VERSION 5.7 ;
  NOWIREEXTENSIONATPIN ON ;
  DIVIDERCHAR "/" ;
  BUSBITCHARS "[]" ;
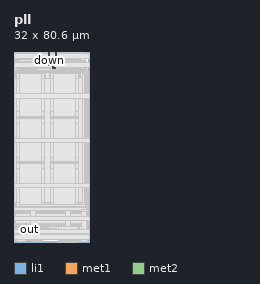
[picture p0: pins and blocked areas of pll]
MACRO pll
  CLASS BLOCK ;
  FOREIGN pll ;
  ORIGIN -0.200 -0.200 ;
  SIZE 32.000 BY 80.600 ;
  PIN down
    DIRECTION INPUT ;
    ANTENNAGATEAREA 0.075000 ;
    PORT
      LAYER li1 ;
        RECT 14.990 75.030 15.320 75.200 ;
      LAYER met1 ;
        RECT 14.900 76.850 15.400 77.350 ;
        RECT 14.950 75.000 15.350 76.850 ;
      LAYER met2 ;
        RECT 14.900 76.850 15.400 80.800 ;
    END
  END down
  PIN up
    DIRECTION INPUT ;
    ANTENNAGATEAREA 0.300000 ;
    PORT
      LAYER li1 ;
        RECT 17.790 75.430 18.120 75.600 ;
        RECT 17.310 73.790 17.640 73.960 ;
      LAYER met1 ;
        RECT 17.750 75.400 18.200 75.750 ;
        RECT 16.950 73.650 17.650 74.050 ;
      LAYER met2 ;
        RECT 17.800 75.750 18.300 80.800 ;
        RECT 16.600 75.350 18.300 75.750 ;
        RECT 16.600 74.050 16.800 75.350 ;
        RECT 16.600 73.650 17.600 74.050 ;
    END
  END up
  PIN out
    DIRECTION OUTPUT ;
    USE CLOCK ;
    ANTENNADIFFAREA 0.310300 ;
    PORT
      LAYER li1 ;
        RECT 6.310 4.930 6.770 5.100 ;
        RECT 6.290 4.090 6.980 4.260 ;
      LAYER met1 ;
        RECT 6.330 4.900 6.750 5.130 ;
        RECT 6.350 4.290 6.900 4.900 ;
        RECT 6.310 4.060 6.960 4.290 ;
        RECT 6.350 4.050 6.900 4.060 ;
      LAYER met2 ;
        RECT 6.350 4.250 6.900 6.650 ;
    END
  END out
  OBS
      LAYER nwell ;
        RECT 18.950 76.290 24.650 76.350 ;
      LAYER pwell ;
        RECT 14.100 73.600 16.210 75.890 ;
      LAYER nwell ;
        RECT 16.400 73.100 24.650 76.290 ;
        RECT 18.950 73.050 24.650 73.100 ;
      LAYER pwell ;
        RECT 0.200 6.800 31.700 72.750 ;
        RECT 0.200 6.750 31.390 6.800 ;
      LAYER nwell ;
        RECT 6.000 4.200 8.500 4.500 ;
      LAYER pwell ;
        RECT 8.500 4.200 12.400 6.450 ;
      LAYER nwell ;
        RECT 6.000 3.200 8.550 4.200 ;
        RECT 7.000 3.150 8.550 3.200 ;
      LAYER pwell ;
        RECT 8.550 3.150 12.400 4.200 ;
        RECT 8.500 0.550 12.400 3.150 ;
      LAYER nwell ;
        RECT 15.750 5.200 17.650 5.210 ;
        RECT 19.200 5.200 27.100 6.150 ;
        RECT 15.750 1.910 27.100 5.200 ;
        RECT 17.600 1.900 27.100 1.910 ;
        RECT 19.200 0.200 27.100 1.900 ;
      LAYER pwell ;
        RECT 28.300 1.850 30.410 5.140 ;
      LAYER li1 ;
        RECT 1.050 80.300 28.050 80.600 ;
        RECT 1.050 77.900 1.350 80.300 ;
        RECT 1.650 79.200 2.150 79.700 ;
        RECT 1.650 78.450 2.150 78.950 ;
        RECT 27.750 77.900 28.050 80.300 ;
        RECT 1.050 77.600 28.050 77.900 ;
        RECT 2.600 76.650 13.100 76.950 ;
        RECT 25.620 76.750 30.660 76.920 ;
        RECT 2.600 73.050 2.900 76.650 ;
        RECT 3.550 76.020 3.880 76.190 ;
        RECT 4.650 76.020 4.980 76.190 ;
        RECT 10.650 76.020 10.980 76.190 ;
        RECT 11.750 76.020 12.080 76.190 ;
        RECT 3.360 74.810 3.530 75.850 ;
        RECT 3.900 74.810 4.070 75.850 ;
        RECT 4.460 74.810 4.630 75.850 ;
        RECT 5.000 74.810 5.170 75.850 ;
        RECT 6.290 75.080 6.620 75.250 ;
        RECT 7.370 75.080 7.700 75.250 ;
        RECT 8.450 75.080 8.780 75.250 ;
        RECT 9.530 75.080 9.860 75.250 ;
        RECT 5.560 73.870 5.730 74.910 ;
        RECT 6.100 73.870 6.270 74.910 ;
        RECT 6.640 73.870 6.810 74.910 ;
        RECT 7.180 73.870 7.350 74.910 ;
        RECT 7.720 73.870 7.890 74.910 ;
        RECT 8.260 73.870 8.430 74.910 ;
        RECT 8.800 73.870 8.970 74.910 ;
        RECT 9.340 73.870 9.510 74.910 ;
        RECT 9.880 73.870 10.050 74.910 ;
        RECT 10.460 74.810 10.630 75.850 ;
        RECT 11.000 74.810 11.170 75.850 ;
        RECT 11.560 74.810 11.730 75.850 ;
        RECT 12.100 74.810 12.270 75.850 ;
        RECT 5.750 73.530 6.080 73.700 ;
        RECT 6.830 73.530 7.160 73.700 ;
        RECT 7.910 73.530 8.240 73.700 ;
        RECT 8.990 73.530 9.320 73.700 ;
        RECT 12.800 73.050 13.100 76.650 ;
        RECT 16.580 75.940 18.850 76.110 ;
        RECT 14.280 75.540 16.030 75.710 ;
        RECT 14.280 73.950 14.450 75.540 ;
        RECT 14.850 74.320 15.020 74.860 ;
        RECT 15.290 74.320 15.460 74.860 ;
        RECT 15.860 73.950 16.030 75.540 ;
        RECT 14.280 73.780 16.030 73.950 ;
        RECT 16.580 73.450 16.750 75.940 ;
        RECT 17.150 74.175 17.320 75.215 ;
        RECT 17.630 74.175 17.800 75.215 ;
        RECT 18.110 74.175 18.280 75.215 ;
        RECT 18.680 73.450 18.850 75.940 ;
        RECT 16.580 73.280 18.850 73.450 ;
        RECT 19.150 75.850 24.450 76.150 ;
        RECT 19.150 73.550 19.450 75.850 ;
        RECT 19.980 75.195 20.310 75.365 ;
        RECT 21.080 75.195 21.410 75.365 ;
        RECT 22.180 75.195 22.510 75.365 ;
        RECT 23.280 75.195 23.610 75.365 ;
        RECT 19.790 73.940 19.960 74.980 ;
        RECT 20.330 73.940 20.500 74.980 ;
        RECT 20.890 73.940 21.060 74.980 ;
        RECT 21.430 73.940 21.600 74.980 ;
        RECT 21.990 73.940 22.160 74.980 ;
        RECT 22.530 73.940 22.700 74.980 ;
        RECT 23.090 73.940 23.260 74.980 ;
        RECT 23.630 73.940 23.800 74.980 ;
        RECT 24.150 73.550 24.450 75.850 ;
        RECT 25.280 73.690 25.450 76.690 ;
        RECT 30.830 73.690 31.000 76.690 ;
        RECT 19.150 73.250 24.450 73.550 ;
        RECT 25.620 73.460 30.660 73.630 ;
        RECT 2.600 72.750 13.100 73.050 ;
        RECT 0.380 72.180 13.980 72.350 ;
        RECT 0.380 14.600 0.550 72.180 ;
        RECT 1.180 71.670 13.180 71.840 ;
        RECT 0.950 69.650 1.120 71.500 ;
        RECT 13.240 69.650 13.410 71.500 ;
        RECT 13.810 69.650 13.980 72.180 ;
        RECT 14.880 72.180 28.480 72.350 ;
        RECT 14.880 69.650 15.050 72.180 ;
        RECT 15.680 71.670 27.680 71.840 ;
        RECT 15.450 69.650 15.620 71.500 ;
        RECT 27.740 69.650 27.910 71.500 ;
        RECT 0.900 55.350 28.000 69.650 ;
        RECT 0.950 53.460 1.120 55.350 ;
        RECT 13.240 53.460 13.410 55.350 ;
        RECT 1.180 53.120 13.180 53.290 ;
        RECT 1.180 52.580 13.180 52.750 ;
        RECT 0.950 50.550 1.120 52.410 ;
        RECT 13.240 50.550 13.410 52.410 ;
        RECT 13.810 50.550 13.980 55.350 ;
        RECT 14.880 50.550 15.050 55.350 ;
        RECT 15.450 53.460 15.620 55.350 ;
        RECT 27.740 53.460 27.910 55.350 ;
        RECT 15.680 53.120 27.680 53.290 ;
        RECT 15.680 52.580 27.680 52.750 ;
        RECT 15.450 50.550 15.620 52.410 ;
        RECT 27.740 50.550 27.910 52.410 ;
        RECT 0.900 36.250 28.000 50.550 ;
        RECT 0.950 34.370 1.120 36.250 ;
        RECT 13.240 34.370 13.410 36.250 ;
        RECT 1.180 34.030 13.180 34.200 ;
        RECT 1.180 33.490 13.180 33.660 ;
        RECT 0.950 31.450 1.120 33.320 ;
        RECT 13.240 31.450 13.410 33.320 ;
        RECT 13.810 31.450 13.980 36.250 ;
        RECT 14.880 31.450 15.050 36.250 ;
        RECT 15.450 34.370 15.620 36.250 ;
        RECT 27.740 34.370 27.910 36.250 ;
        RECT 15.680 34.030 27.680 34.200 ;
        RECT 15.680 33.490 27.680 33.660 ;
        RECT 15.450 31.450 15.620 33.320 ;
        RECT 27.740 31.450 27.910 33.320 ;
        RECT 0.900 17.150 28.000 31.450 ;
        RECT 0.950 15.280 1.120 17.150 ;
        RECT 13.240 15.280 13.410 17.150 ;
        RECT 1.180 14.940 13.180 15.110 ;
        RECT 13.810 14.600 13.980 17.150 ;
        RECT 0.380 14.430 13.980 14.600 ;
        RECT 14.880 14.600 15.050 17.150 ;
        RECT 15.450 15.280 15.620 17.150 ;
        RECT 27.740 15.280 27.910 17.150 ;
        RECT 15.680 14.940 27.680 15.110 ;
        RECT 28.310 14.600 28.480 72.180 ;
        RECT 14.880 14.430 28.480 14.600 ;
        RECT 29.100 72.250 31.200 72.550 ;
        RECT 29.100 14.750 29.400 72.250 ;
        RECT 29.800 71.150 30.500 71.850 ;
        RECT 29.800 15.150 30.500 15.850 ;
        RECT 30.900 14.750 31.200 72.250 ;
        RECT 29.100 14.450 31.200 14.750 ;
        RECT 0.380 13.360 31.210 13.530 ;
        RECT 0.380 7.100 0.550 13.360 ;
        RECT 2.600 12.960 13.900 13.360 ;
        RECT 17.700 12.960 29.000 13.360 ;
        RECT 1.230 12.790 15.270 12.960 ;
        RECT 16.320 12.790 30.360 12.960 ;
        RECT 0.890 7.730 1.060 12.730 ;
        RECT 2.600 7.670 13.900 12.790 ;
        RECT 15.440 7.730 15.610 12.730 ;
        RECT 15.980 7.730 16.150 12.730 ;
        RECT 17.700 7.670 29.000 12.790 ;
        RECT 30.530 7.730 30.700 12.730 ;
        RECT 1.230 7.500 15.270 7.670 ;
        RECT 16.320 7.500 30.360 7.670 ;
        RECT 2.600 7.100 13.900 7.500 ;
        RECT 17.700 7.100 29.000 7.500 ;
        RECT 31.040 7.100 31.210 13.360 ;
        RECT 0.380 6.930 31.210 7.100 ;
        RECT 8.700 5.750 12.200 6.250 ;
        RECT 13.650 5.800 18.150 5.810 ;
        RECT 1.140 5.230 5.140 5.400 ;
        RECT 6.310 5.370 6.770 5.540 ;
        RECT 6.940 5.070 7.110 5.400 ;
        RECT 0.910 1.020 1.080 5.060 ;
        RECT 5.200 1.020 5.370 5.060 ;
        RECT 6.290 3.650 6.980 3.820 ;
        RECT 7.195 3.790 7.365 4.120 ;
        RECT 7.650 3.400 8.300 3.900 ;
        RECT 8.700 1.250 9.200 5.750 ;
        RECT 9.610 5.200 10.650 5.370 ;
        RECT 9.610 4.760 10.650 4.930 ;
        RECT 10.820 4.900 10.990 5.230 ;
        RECT 9.610 4.200 10.650 4.370 ;
        RECT 9.610 3.760 10.650 3.930 ;
        RECT 10.820 3.900 10.990 4.230 ;
        RECT 9.610 3.200 10.650 3.370 ;
        RECT 9.610 2.760 10.650 2.930 ;
        RECT 10.820 2.900 10.990 3.230 ;
        RECT 9.610 2.200 10.650 2.370 ;
        RECT 9.610 1.760 10.650 1.930 ;
        RECT 10.820 1.900 10.990 2.230 ;
        RECT 11.700 1.250 12.200 5.750 ;
        RECT 13.550 5.510 18.150 5.800 ;
        RECT 13.550 5.500 13.950 5.510 ;
        RECT 17.850 5.500 18.150 5.510 ;
        RECT 19.450 5.500 26.800 5.900 ;
        RECT 13.550 1.600 13.900 5.500 ;
        RECT 14.360 4.780 15.050 4.950 ;
        RECT 14.360 4.340 15.050 4.510 ;
        RECT 15.220 4.480 15.390 4.810 ;
        RECT 15.845 4.500 16.015 4.830 ;
        RECT 16.230 4.800 17.270 4.970 ;
        RECT 16.230 4.360 17.270 4.530 ;
        RECT 14.360 3.680 15.050 3.850 ;
        RECT 14.360 3.240 15.050 3.410 ;
        RECT 15.220 3.380 15.390 3.710 ;
        RECT 15.845 3.400 16.015 3.730 ;
        RECT 16.230 3.700 17.270 3.870 ;
        RECT 16.230 3.260 17.270 3.430 ;
        RECT 18.050 3.200 19.000 4.800 ;
        RECT 14.360 2.580 15.050 2.750 ;
        RECT 14.360 2.140 15.050 2.310 ;
        RECT 15.220 2.280 15.390 2.610 ;
        RECT 15.845 2.300 16.015 2.630 ;
        RECT 16.230 2.600 17.270 2.770 ;
        RECT 16.230 2.160 17.270 2.330 ;
        RECT 14.200 1.600 17.700 1.610 ;
        RECT 13.550 1.250 18.150 1.600 ;
        RECT 1.140 0.680 5.140 0.850 ;
        RECT 8.700 0.750 12.200 1.250 ;
        RECT 19.450 0.900 19.900 5.500 ;
        RECT 20.390 4.730 25.430 4.900 ;
        RECT 20.390 4.290 25.430 4.460 ;
        RECT 25.645 4.430 25.815 4.760 ;
        RECT 20.390 3.730 25.430 3.900 ;
        RECT 20.390 3.290 25.430 3.460 ;
        RECT 25.645 3.430 25.815 3.760 ;
        RECT 20.390 2.730 25.430 2.900 ;
        RECT 20.390 2.290 25.430 2.460 ;
        RECT 25.645 2.430 25.815 2.760 ;
        RECT 20.390 1.730 25.430 1.900 ;
        RECT 20.390 1.290 25.430 1.460 ;
        RECT 25.645 1.430 25.815 1.760 ;
        RECT 26.350 0.900 26.800 5.500 ;
        RECT 28.480 4.790 30.230 4.960 ;
        RECT 28.480 2.200 28.650 4.790 ;
        RECT 29.190 4.280 29.520 4.450 ;
        RECT 29.050 2.570 29.220 4.110 ;
        RECT 29.490 2.570 29.660 4.110 ;
        RECT 30.060 2.200 30.230 4.790 ;
        RECT 28.480 2.030 30.230 2.200 ;
        RECT 19.450 0.450 26.800 0.900 ;
      LAYER met1 ;
        RECT 0.300 80.300 30.600 80.600 ;
        RECT 0.300 77.900 1.350 80.300 ;
        RECT 1.650 79.200 2.150 79.700 ;
        RECT 1.650 78.450 2.150 78.950 ;
        RECT 27.750 77.900 30.600 80.300 ;
        RECT 0.300 77.600 30.600 77.900 ;
        RECT 0.300 76.650 14.750 77.600 ;
        RECT 15.850 77.250 30.600 77.600 ;
        RECT 0.300 74.550 2.900 76.650 ;
        RECT 3.500 76.000 6.150 76.350 ;
        RECT 9.900 76.050 12.100 76.350 ;
        RECT 9.850 76.000 12.100 76.050 ;
        RECT 3.570 75.990 3.860 76.000 ;
        RECT 4.670 75.990 4.960 76.000 ;
        RECT 3.300 74.850 3.700 75.850 ;
        RECT 3.870 75.800 4.100 75.830 ;
        RECT 4.430 75.800 4.660 75.830 ;
        RECT 3.330 74.830 3.560 74.850 ;
        RECT 3.870 74.830 4.660 75.800 ;
        RECT 4.800 74.850 5.200 75.850 ;
        RECT 9.850 75.500 10.000 76.000 ;
        RECT 10.670 75.990 10.960 76.000 ;
        RECT 11.770 75.990 12.060 76.000 ;
        RECT 6.200 75.125 10.000 75.500 ;
        RECT 6.100 75.090 10.000 75.125 ;
        RECT 6.070 75.050 10.000 75.090 ;
        RECT 6.070 74.890 6.295 75.050 ;
        RECT 7.150 74.890 7.375 75.050 ;
        RECT 8.230 74.890 8.455 75.050 ;
        RECT 9.315 74.890 9.540 75.050 ;
        RECT 5.530 74.850 5.760 74.890 ;
        RECT 4.970 74.830 5.200 74.850 ;
        RECT 3.900 74.550 4.650 74.830 ;
        RECT 5.350 74.550 5.760 74.850 ;
        RECT 0.300 73.890 5.760 74.550 ;
        RECT 6.070 73.890 6.300 74.890 ;
        RECT 6.610 74.850 6.840 74.890 ;
        RECT 6.450 73.890 6.840 74.850 ;
        RECT 7.150 73.890 7.380 74.890 ;
        RECT 7.690 74.850 7.920 74.890 ;
        RECT 7.550 73.890 7.920 74.850 ;
        RECT 8.230 73.890 8.460 74.890 ;
        RECT 8.770 74.850 9.000 74.890 ;
        RECT 8.600 73.890 9.000 74.850 ;
        RECT 9.310 73.890 9.540 74.890 ;
        RECT 9.850 74.550 10.080 74.890 ;
        RECT 10.400 74.850 10.800 75.850 ;
        RECT 10.970 75.800 11.200 75.830 ;
        RECT 11.530 75.800 11.760 75.830 ;
        RECT 10.430 74.830 10.660 74.850 ;
        RECT 10.970 74.830 11.760 75.800 ;
        RECT 11.900 74.850 12.300 75.850 ;
        RECT 12.070 74.830 12.300 74.850 ;
        RECT 12.800 75.500 14.750 76.650 ;
        RECT 15.850 76.550 19.450 77.000 ;
        RECT 25.650 76.950 30.600 77.250 ;
        RECT 25.640 76.720 30.640 76.950 ;
        RECT 25.250 76.650 25.480 76.670 ;
        RECT 20.000 76.500 25.480 76.650 ;
        RECT 30.800 76.500 31.030 76.670 ;
        RECT 20.000 76.150 31.030 76.500 ;
        RECT 16.550 75.900 31.030 76.150 ;
        RECT 15.550 75.500 16.100 75.750 ;
        RECT 11.000 74.550 11.750 74.830 ;
        RECT 12.800 74.550 14.500 75.500 ;
        RECT 9.850 74.000 14.500 74.550 ;
        RECT 14.650 74.200 15.050 74.850 ;
        RECT 15.250 74.250 15.650 74.850 ;
        RECT 15.800 74.000 16.100 75.500 ;
        RECT 9.850 73.890 16.100 74.000 ;
        RECT 0.300 73.050 5.500 73.890 ;
        RECT 5.750 73.700 6.080 73.750 ;
        RECT 5.700 73.250 6.130 73.700 ;
        RECT 6.450 73.050 6.600 73.890 ;
        RECT 6.830 73.700 7.160 73.750 ;
        RECT 6.775 73.250 7.205 73.700 ;
        RECT 7.550 73.050 7.700 73.890 ;
        RECT 7.910 73.700 8.240 73.750 ;
        RECT 7.860 73.250 8.290 73.700 ;
        RECT 8.600 73.050 8.750 73.890 ;
        RECT 9.100 73.730 9.320 73.750 ;
        RECT 9.010 73.700 9.320 73.730 ;
        RECT 8.950 73.650 9.300 73.700 ;
        RECT 8.985 73.300 9.320 73.650 ;
        RECT 9.900 73.050 16.100 73.890 ;
        RECT 16.550 73.500 16.800 75.900 ;
        RECT 18.650 75.850 31.030 75.900 ;
        RECT 16.950 75.195 17.300 75.200 ;
        RECT 16.950 74.250 17.350 75.195 ;
        RECT 17.600 74.795 17.830 75.195 ;
        RECT 18.080 75.150 18.310 75.195 ;
        RECT 17.100 74.200 17.350 74.250 ;
        RECT 17.120 74.195 17.350 74.200 ;
        RECT 17.545 74.195 17.885 74.795 ;
        RECT 18.080 74.200 18.500 75.150 ;
        RECT 18.080 74.195 18.310 74.200 ;
        RECT 18.650 73.550 19.450 75.850 ;
        RECT 19.650 75.150 20.500 75.700 ;
        RECT 21.100 75.395 22.450 75.450 ;
        RECT 21.100 75.165 22.490 75.395 ;
        RECT 21.100 75.150 22.450 75.165 ;
        RECT 23.100 75.150 24.000 75.700 ;
        RECT 21.450 74.960 22.150 75.150 ;
        RECT 19.760 74.950 19.990 74.960 ;
        RECT 20.300 74.950 20.530 74.960 ;
        RECT 19.600 73.900 20.000 74.950 ;
        RECT 20.300 74.900 20.700 74.950 ;
        RECT 20.860 74.900 21.090 74.960 ;
        RECT 20.300 73.960 21.090 74.900 ;
        RECT 21.400 73.960 22.190 74.960 ;
        RECT 22.500 74.950 22.730 74.960 ;
        RECT 23.060 74.950 23.290 74.960 ;
        RECT 23.600 74.950 23.830 74.960 ;
        RECT 22.500 73.960 23.300 74.950 ;
        RECT 20.300 73.950 21.050 73.960 ;
        RECT 21.450 73.950 22.150 73.960 ;
        RECT 22.550 73.950 23.300 73.960 ;
        RECT 20.550 73.550 21.050 73.950 ;
        RECT 22.550 73.550 23.050 73.950 ;
        RECT 23.600 73.900 24.000 74.950 ;
        RECT 24.150 73.900 31.030 75.850 ;
        RECT 24.150 73.710 25.480 73.900 ;
        RECT 30.800 73.710 31.030 73.900 ;
        RECT 24.150 73.700 25.300 73.710 ;
        RECT 24.150 73.550 24.450 73.700 ;
        RECT 25.640 73.600 30.640 73.660 ;
        RECT 25.640 73.550 30.650 73.600 ;
        RECT 18.650 73.500 24.450 73.550 ;
        RECT 16.550 73.250 24.450 73.500 ;
        RECT 0.300 72.450 16.100 73.050 ;
        RECT 24.950 72.450 31.200 73.550 ;
        RECT 0.300 72.250 31.200 72.450 ;
        RECT 0.300 72.150 29.400 72.250 ;
        RECT 0.300 69.750 0.650 72.150 ;
        RECT 2.385 71.640 11.975 71.870 ;
        RECT 0.300 63.200 1.150 69.750 ;
        RECT 0.200 61.200 2.100 63.200 ;
        RECT 0.300 44.200 1.150 61.200 ;
        RECT 2.400 53.320 11.900 71.640 ;
        RECT 13.700 69.700 15.150 72.150 ;
        RECT 16.885 71.640 26.475 71.870 ;
        RECT 2.385 53.090 11.975 53.320 ;
        RECT 2.400 52.780 11.900 53.090 ;
        RECT 2.385 52.550 11.975 52.780 ;
        RECT 0.200 42.200 2.100 44.200 ;
        RECT 0.300 25.200 1.150 42.200 ;
        RECT 2.400 34.230 11.900 52.550 ;
        RECT 2.385 34.000 11.975 34.230 ;
        RECT 2.400 33.690 11.900 34.000 ;
        RECT 2.385 33.460 11.975 33.690 ;
        RECT 0.200 23.200 2.100 25.200 ;
        RECT 0.300 16.850 1.150 23.200 ;
        RECT 0.300 14.630 0.650 16.850 ;
        RECT 2.400 15.140 11.900 33.460 ;
        RECT 13.150 17.100 15.700 69.700 ;
        RECT 16.900 53.320 26.400 71.640 ;
        RECT 28.200 69.950 29.400 72.150 ;
        RECT 29.800 71.150 30.500 71.850 ;
        RECT 27.700 63.200 29.400 69.950 ;
        RECT 27.200 61.200 29.400 63.200 ;
        RECT 16.885 53.090 26.475 53.320 ;
        RECT 16.900 52.780 26.400 53.090 ;
        RECT 16.885 52.550 26.475 52.780 ;
        RECT 16.900 34.230 26.400 52.550 ;
        RECT 27.700 44.200 29.400 61.200 ;
        RECT 27.200 42.200 29.400 44.200 ;
        RECT 16.885 34.000 26.475 34.230 ;
        RECT 16.900 33.690 26.400 34.000 ;
        RECT 16.885 33.460 26.475 33.690 ;
        RECT 13.210 17.090 13.440 17.100 ;
        RECT 2.385 14.910 11.975 15.140 ;
        RECT 13.700 14.630 15.150 17.100 ;
        RECT 15.420 17.090 15.650 17.100 ;
        RECT 16.900 15.140 26.400 33.460 ;
        RECT 27.700 25.200 29.400 42.200 ;
        RECT 27.200 23.200 29.400 25.200 ;
        RECT 27.700 17.050 29.400 23.200 ;
        RECT 16.885 14.910 26.475 15.140 ;
        RECT 28.200 14.750 29.400 17.050 ;
        RECT 29.700 15.050 30.600 15.950 ;
        RECT 30.900 14.750 31.200 72.250 ;
        RECT 28.200 14.630 31.200 14.750 ;
        RECT 0.300 13.650 31.200 14.630 ;
        RECT 0.300 13.300 31.300 13.650 ;
        RECT 0.300 7.200 0.580 13.300 ;
        RECT 2.200 12.700 14.200 13.300 ;
        RECT 17.200 12.700 29.200 13.300 ;
        RECT 0.860 12.150 1.090 12.225 ;
        RECT 15.410 12.150 15.640 12.225 ;
        RECT 15.950 12.150 16.180 12.225 ;
        RECT 30.500 12.150 30.730 12.225 ;
        RECT 0.860 8.250 30.730 12.150 ;
        RECT 0.860 8.235 1.090 8.250 ;
        RECT 15.410 8.235 15.640 8.250 ;
        RECT 15.950 8.235 16.180 8.250 ;
        RECT 30.500 8.235 30.730 8.250 ;
        RECT 2.200 7.200 14.200 7.700 ;
        RECT 17.200 7.200 29.200 7.700 ;
        RECT 31.010 7.200 31.300 13.300 ;
        RECT 0.300 6.850 31.300 7.200 ;
        RECT 0.300 5.150 0.850 6.850 ;
        RECT 1.150 5.350 6.050 6.350 ;
        RECT 6.250 5.900 18.150 6.850 ;
        RECT 6.250 5.350 6.750 5.900 ;
        RECT 8.700 5.750 18.150 5.900 ;
        RECT 1.160 5.200 6.050 5.350 ;
        RECT 6.330 5.340 6.750 5.350 ;
        RECT 0.300 5.050 1.000 5.150 ;
        RECT 0.300 5.040 1.050 5.050 ;
        RECT 0.300 1.040 1.110 5.040 ;
        RECT 0.300 0.900 0.950 1.040 ;
        RECT 0.300 0.650 0.850 0.900 ;
        RECT 1.400 0.880 4.850 5.200 ;
        RECT 5.200 5.040 5.550 5.050 ;
        RECT 5.170 3.150 5.550 5.040 ;
        RECT 5.700 3.850 6.050 5.200 ;
        RECT 6.900 5.050 8.450 5.400 ;
        RECT 7.150 4.150 8.450 5.050 ;
        RECT 8.700 4.950 9.200 5.750 ;
        RECT 9.650 5.400 10.600 5.600 ;
        RECT 11.700 5.510 18.150 5.750 ;
        RECT 11.700 5.500 13.950 5.510 ;
        RECT 17.850 5.500 18.150 5.510 ;
        RECT 19.450 5.500 27.700 6.700 ;
        RECT 9.630 5.170 10.630 5.400 ;
        RECT 10.800 5.210 11.500 5.250 ;
        RECT 9.630 4.950 10.630 4.960 ;
        RECT 8.700 4.730 10.630 4.950 ;
        RECT 10.790 4.920 11.500 5.210 ;
        RECT 8.700 4.400 10.600 4.730 ;
        RECT 8.700 4.200 10.630 4.400 ;
        RECT 10.800 4.210 11.500 4.920 ;
        RECT 5.700 3.650 6.960 3.850 ;
        RECT 7.150 3.800 7.400 4.150 ;
        RECT 7.600 3.650 8.350 3.950 ;
        RECT 5.700 3.350 8.350 3.650 ;
        RECT 8.700 3.150 9.200 4.200 ;
        RECT 9.630 4.170 10.630 4.200 ;
        RECT 9.630 3.950 10.630 3.960 ;
        RECT 10.790 3.950 11.500 4.210 ;
        RECT 9.630 3.730 11.500 3.950 ;
        RECT 9.650 3.400 11.500 3.730 ;
        RECT 9.630 3.200 11.500 3.400 ;
        RECT 9.630 3.170 10.630 3.200 ;
        RECT 5.170 2.950 9.200 3.150 ;
        RECT 9.630 2.950 10.630 2.960 ;
        RECT 5.170 2.730 10.630 2.950 ;
        RECT 10.790 2.920 11.500 3.200 ;
        RECT 5.170 2.400 10.600 2.730 ;
        RECT 5.170 2.200 10.630 2.400 ;
        RECT 10.800 2.210 11.500 2.920 ;
        RECT 5.170 1.250 9.200 2.200 ;
        RECT 9.630 2.170 10.630 2.200 ;
        RECT 9.630 1.730 10.630 1.960 ;
        RECT 10.790 1.920 11.500 2.210 ;
        RECT 10.800 1.850 11.500 1.920 ;
        RECT 11.700 3.700 13.900 5.500 ;
        RECT 14.150 5.050 15.050 5.060 ;
        RECT 14.050 4.760 15.050 5.050 ;
        RECT 15.200 4.860 16.000 5.300 ;
        RECT 19.450 5.250 19.900 5.500 ;
        RECT 26.350 5.450 27.700 5.500 ;
        RECT 16.200 5.000 17.350 5.060 ;
        RECT 15.200 4.790 16.050 4.860 ;
        RECT 14.050 3.960 14.200 4.760 ;
        RECT 14.380 4.750 15.030 4.760 ;
        RECT 15.190 4.610 16.050 4.790 ;
        RECT 16.200 4.800 17.700 5.000 ;
        RECT 16.200 4.760 17.350 4.800 ;
        RECT 14.400 4.540 15.050 4.550 ;
        RECT 14.380 4.310 15.050 4.540 ;
        RECT 15.190 4.500 15.420 4.610 ;
        RECT 15.815 4.520 16.045 4.610 ;
        RECT 16.250 4.310 17.250 4.560 ;
        RECT 14.400 4.160 17.350 4.310 ;
        RECT 9.650 1.450 10.600 1.730 ;
        RECT 11.700 1.250 12.200 3.700 ;
        RECT 14.050 3.660 15.050 3.960 ;
        RECT 15.500 3.760 15.750 4.160 ;
        RECT 16.200 3.900 17.350 3.960 ;
        RECT 17.500 3.900 17.700 4.800 ;
        RECT 15.200 3.690 16.050 3.760 ;
        RECT 14.050 3.400 14.200 3.660 ;
        RECT 14.380 3.650 15.030 3.660 ;
        RECT 14.400 3.450 15.000 3.460 ;
        RECT 14.400 3.440 15.050 3.450 ;
        RECT 12.550 3.200 14.200 3.400 ;
        RECT 14.380 3.210 15.050 3.440 ;
        RECT 15.190 3.400 16.050 3.690 ;
        RECT 16.200 3.700 17.700 3.900 ;
        RECT 16.200 3.660 17.350 3.700 ;
        RECT 15.200 3.360 16.050 3.400 ;
        RECT 16.200 3.210 17.350 3.460 ;
        RECT 12.550 1.850 12.900 3.200 ;
        RECT 12.500 1.400 12.950 1.850 ;
        RECT 13.550 1.600 13.900 2.900 ;
        RECT 14.050 2.860 14.200 3.200 ;
        RECT 14.400 3.060 17.350 3.210 ;
        RECT 14.050 2.560 15.050 2.860 ;
        RECT 15.500 2.660 15.750 3.060 ;
        RECT 16.200 2.800 17.350 2.860 ;
        RECT 17.500 2.800 17.700 3.700 ;
        RECT 18.050 4.800 19.900 5.250 ;
        RECT 18.050 3.200 19.000 4.800 ;
        RECT 19.450 2.950 19.900 4.800 ;
        RECT 20.050 4.930 25.400 5.150 ;
        RECT 20.050 4.750 25.410 4.930 ;
        RECT 20.050 2.800 20.200 4.750 ;
        RECT 20.410 4.700 25.410 4.750 ;
        RECT 20.450 4.490 25.400 4.500 ;
        RECT 20.410 4.260 25.410 4.490 ;
        RECT 20.450 3.930 25.400 4.260 ;
        RECT 20.410 3.700 25.410 3.930 ;
        RECT 25.600 3.500 26.250 4.800 ;
        RECT 20.450 3.490 26.250 3.500 ;
        RECT 20.410 3.260 26.250 3.490 ;
        RECT 20.450 2.930 26.250 3.260 ;
        RECT 15.200 2.590 16.050 2.660 ;
        RECT 14.050 2.550 14.200 2.560 ;
        RECT 14.380 2.550 15.030 2.560 ;
        RECT 14.400 2.350 15.000 2.360 ;
        RECT 14.400 2.340 15.050 2.350 ;
        RECT 14.380 2.110 15.050 2.340 ;
        RECT 15.190 2.300 16.050 2.590 ;
        RECT 16.200 2.600 20.200 2.800 ;
        RECT 20.410 2.700 26.250 2.930 ;
        RECT 16.200 2.560 17.350 2.600 ;
        RECT 15.200 2.260 16.050 2.300 ;
        RECT 16.200 2.110 17.350 2.360 ;
        RECT 14.400 1.960 17.350 2.110 ;
        RECT 14.400 1.750 15.400 1.960 ;
        RECT 14.200 1.600 17.700 1.610 ;
        RECT 13.550 1.250 18.150 1.600 ;
        RECT 5.170 1.040 12.200 1.250 ;
        RECT 1.160 0.650 5.120 0.880 ;
        RECT 5.350 0.750 12.200 1.040 ;
        RECT 19.450 0.900 19.900 2.450 ;
        RECT 20.050 1.450 20.200 2.600 ;
        RECT 20.450 2.490 25.400 2.500 ;
        RECT 20.410 2.260 25.410 2.490 ;
        RECT 20.450 1.930 25.400 2.260 ;
        RECT 20.410 1.700 25.410 1.930 ;
        RECT 20.450 1.490 25.400 1.500 ;
        RECT 20.410 1.450 25.410 1.490 ;
        RECT 20.050 1.260 25.410 1.450 ;
        RECT 25.600 1.400 26.250 2.700 ;
        RECT 20.050 1.050 25.400 1.260 ;
        RECT 26.400 0.950 27.700 5.450 ;
        RECT 26.350 0.900 27.700 0.950 ;
        RECT 19.450 0.450 27.700 0.900 ;
        RECT 28.150 5.300 31.300 6.850 ;
        RECT 28.150 2.250 28.700 5.300 ;
        RECT 29.000 4.250 29.800 5.150 ;
        RECT 28.850 2.600 29.250 4.100 ;
        RECT 29.450 2.600 29.850 4.100 ;
        RECT 29.020 2.590 29.250 2.600 ;
        RECT 29.460 2.590 29.690 2.600 ;
        RECT 30.000 2.250 31.300 5.300 ;
        RECT 28.150 2.000 31.300 2.250 ;
        RECT 28.150 0.300 28.250 2.000 ;
        RECT 30.200 1.650 31.200 2.000 ;
        RECT 28.300 0.400 31.200 1.650 ;
      LAYER met2 ;
        RECT 0.400 78.200 0.900 80.200 ;
        RECT 1.100 79.200 2.150 79.700 ;
        RECT 1.100 77.000 1.400 79.200 ;
        RECT 0.700 74.200 1.400 77.000 ;
        RECT 1.650 73.700 2.150 78.950 ;
        RECT 28.200 77.200 30.500 80.500 ;
        RECT 15.850 76.600 16.300 77.000 ;
        RECT 3.300 76.250 16.300 76.600 ;
        RECT 19.000 76.600 19.450 77.000 ;
        RECT 19.000 76.250 20.650 76.600 ;
        RECT 3.300 76.200 12.300 76.250 ;
        RECT 3.300 74.850 3.700 76.200 ;
        RECT 4.800 75.600 10.800 76.000 ;
        RECT 4.800 74.850 5.200 75.600 ;
        RECT 6.100 75.050 10.000 75.450 ;
        RECT 6.100 73.700 6.250 75.050 ;
        RECT 7.200 73.700 7.350 75.050 ;
        RECT 8.250 73.700 8.400 75.050 ;
        RECT 9.350 73.700 9.500 75.050 ;
        RECT 10.400 74.050 10.800 75.600 ;
        RECT 11.900 74.850 12.300 76.200 ;
        RECT 20.350 75.700 20.650 76.250 ;
        RECT 16.950 75.000 19.050 75.200 ;
        RECT 19.600 75.150 24.000 75.700 ;
        RECT 13.600 74.200 15.050 74.850 ;
        RECT 15.300 74.250 16.350 74.850 ;
        RECT 16.950 74.250 17.350 75.000 ;
        RECT 18.100 74.950 19.050 75.000 ;
        RECT 13.600 74.050 14.000 74.200 ;
        RECT 10.400 73.700 14.000 74.050 ;
        RECT 1.650 73.250 9.500 73.700 ;
        RECT 15.700 73.100 16.350 74.250 ;
        RECT 17.500 74.200 17.950 74.800 ;
        RECT 18.100 74.200 24.000 74.950 ;
        RECT 17.750 74.050 17.950 74.200 ;
        RECT 17.750 73.100 18.100 74.050 ;
        RECT 18.850 73.900 24.000 74.200 ;
        RECT 25.650 73.950 30.650 76.450 ;
        RECT 15.700 72.550 30.400 73.100 ;
        RECT 29.900 71.950 30.400 72.550 ;
        RECT 29.700 71.050 30.600 71.950 ;
        RECT 0.200 61.200 2.200 63.200 ;
        RECT 13.200 61.200 15.700 63.200 ;
        RECT 27.200 61.200 29.200 63.200 ;
        RECT 0.200 42.200 2.200 44.200 ;
        RECT 13.200 42.200 15.700 44.200 ;
        RECT 27.200 42.200 29.200 44.200 ;
        RECT 0.200 23.200 2.200 25.200 ;
        RECT 13.200 23.200 15.700 25.200 ;
        RECT 27.200 23.200 29.200 25.200 ;
        RECT 29.900 17.000 30.400 71.050 ;
        RECT 29.900 16.500 31.550 17.000 ;
        RECT 2.400 15.350 30.600 16.150 ;
        RECT 29.600 15.050 30.600 15.350 ;
        RECT 31.000 14.000 31.550 16.500 ;
        RECT 7.200 12.800 9.200 13.600 ;
        RECT 22.200 12.800 24.200 13.600 ;
        RECT 28.900 12.950 31.550 14.000 ;
        RECT 7.200 6.900 9.200 7.700 ;
        RECT 22.200 6.980 24.200 7.700 ;
        RECT 7.550 5.950 14.800 6.450 ;
        RECT 1.150 0.600 5.250 5.600 ;
        RECT 7.550 4.250 8.400 5.950 ;
        RECT 8.700 5.500 10.600 5.650 ;
        RECT 5.650 0.750 8.500 3.150 ;
        RECT 8.700 1.800 9.250 5.500 ;
        RECT 9.650 5.250 10.600 5.500 ;
        RECT 14.400 5.300 14.800 5.950 ;
        RECT 14.400 4.800 16.000 5.300 ;
        RECT 10.950 2.800 11.450 3.700 ;
        RECT 10.950 2.300 13.400 2.800 ;
        RECT 12.500 1.800 12.950 1.850 ;
        RECT 8.700 1.450 12.950 1.800 ;
        RECT 12.500 1.400 12.950 1.450 ;
        RECT 13.100 1.200 13.400 2.300 ;
        RECT 14.400 1.750 15.100 4.800 ;
        RECT 19.450 4.600 27.700 6.700 ;
        RECT 28.900 5.600 30.900 12.950 ;
        RECT 20.295 1.650 25.410 4.600 ;
        RECT 29.000 4.250 30.400 5.600 ;
        RECT 25.700 3.400 26.100 4.150 ;
        RECT 28.800 3.400 29.200 4.100 ;
        RECT 25.700 3.050 29.200 3.400 ;
        RECT 25.700 2.050 26.100 3.050 ;
        RECT 28.800 2.600 29.200 3.050 ;
        RECT 29.500 2.350 29.900 4.100 ;
        RECT 27.500 1.950 29.900 2.350 ;
        RECT 27.500 1.200 27.900 1.950 ;
        RECT 30.150 1.700 31.250 4.100 ;
        RECT 28.250 0.350 31.250 1.700 ;
      LAYER met3 ;
        RECT 0.200 78.200 32.200 80.200 ;
        RECT 0.200 74.200 32.200 76.200 ;
        RECT 0.200 61.200 32.200 63.200 ;
        RECT 0.200 42.200 32.200 44.200 ;
        RECT 0.200 23.200 32.200 25.200 ;
        RECT 7.200 11.200 9.200 13.700 ;
        RECT 22.200 11.200 24.200 13.700 ;
        RECT 0.200 9.200 32.200 11.200 ;
        RECT 7.200 6.700 9.200 9.200 ;
        RECT 22.200 6.900 24.200 9.200 ;
        RECT 19.200 5.700 27.700 6.600 ;
        RECT 0.200 3.700 32.200 5.700 ;
        RECT 0.200 1.200 32.200 3.200 ;
  END
END pll
END LIBRARY

